VERSION 5.7 ;
  NOWIREEXTENSIONATPIN ON ;
  DIVIDERCHAR "/" ;
  BUSBITCHARS "[]" ;
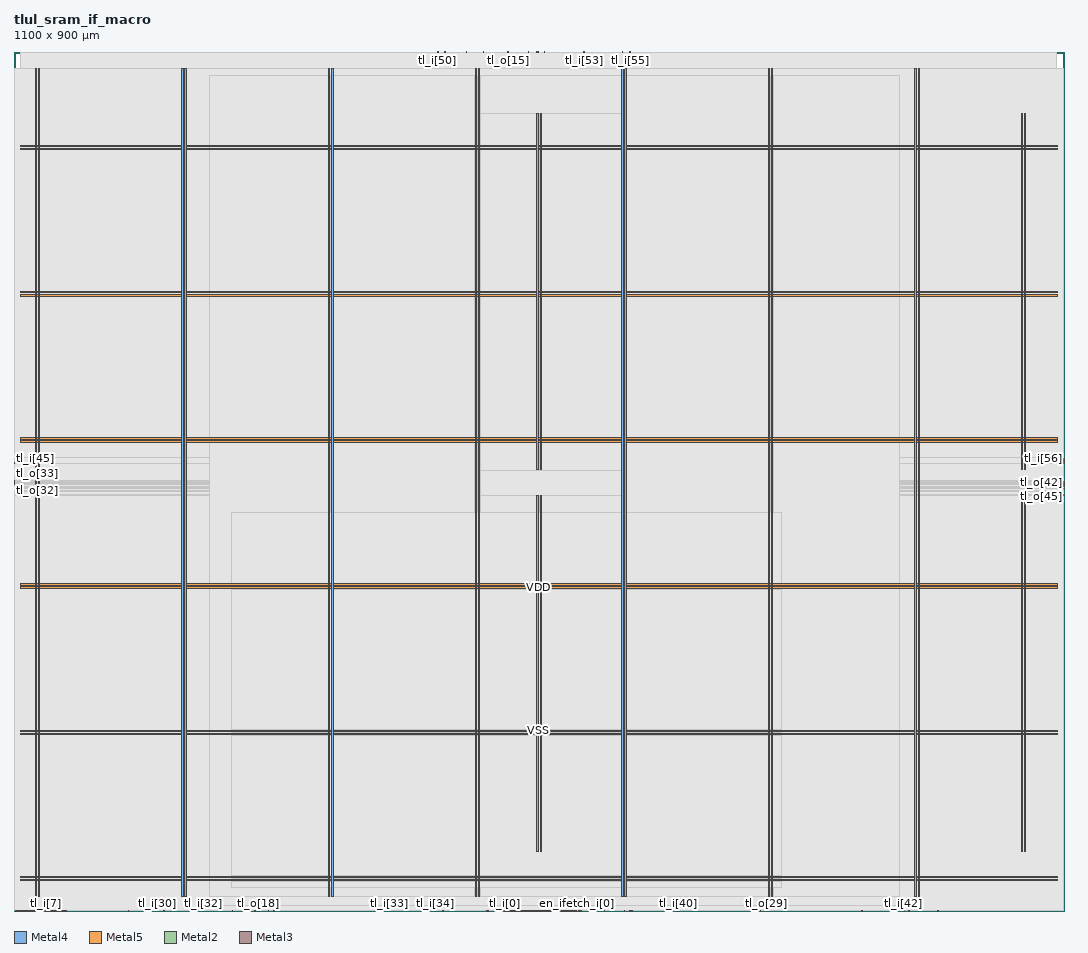
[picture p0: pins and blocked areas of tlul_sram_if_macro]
MACRO tlul_sram_if_macro
  CLASS BLOCK ;
  FOREIGN tlul_sram_if_macro ;
  ORIGIN 0.000 0.000 ;
  SIZE 1100.000 BY 900.000 ;
  PIN VDD
    DIRECTION INOUT ;
    USE POWER ;
    PORT
      LAYER Metal4 ;
        RECT 22.240 15.380 23.840 882.300 ;
    END
    PORT
      LAYER Metal4 ;
        RECT 175.840 15.380 177.440 882.300 ;
    END
    PORT
      LAYER Metal4 ;
        RECT 329.440 15.380 331.040 882.300 ;
    END
    PORT
      LAYER Metal4 ;
        RECT 483.040 15.380 484.640 882.300 ;
    END
    PORT
      LAYER Metal4 ;
        RECT 636.640 15.380 638.240 882.300 ;
    END
    PORT
      LAYER Metal4 ;
        RECT 790.240 15.380 791.840 882.300 ;
    END
    PORT
      LAYER Metal4 ;
        RECT 943.840 15.380 945.440 882.300 ;
    END
    PORT
      LAYER Metal5 ;
        RECT 6.720 31.530 1093.120 33.130 ;
    END
    PORT
      LAYER Metal5 ;
        RECT 6.720 184.710 1093.120 186.310 ;
    END
    PORT
      LAYER Metal5 ;
        RECT 6.720 337.890 1093.120 339.490 ;
    END
    PORT
      LAYER Metal5 ;
        RECT 6.720 491.070 1093.120 492.670 ;
    END
    PORT
      LAYER Metal5 ;
        RECT 6.720 644.250 1093.120 645.850 ;
    END
    PORT
      LAYER Metal5 ;
        RECT 6.720 797.430 1093.120 799.030 ;
    END
    PORT
      LAYER Metal4 ;
        RECT 547.720 62.420 549.320 435.420 ;
    END
    PORT
      LAYER Metal4 ;
        RECT 1055.080 462.260 1056.680 835.260 ;
    END
    PORT
      LAYER Metal4 ;
        RECT 547.720 462.260 549.320 835.260 ;
    END
    PORT
      LAYER Metal4 ;
        RECT 1055.080 62.420 1056.680 435.420 ;
    END
  END VDD
  PIN VSS
    DIRECTION INOUT ;
    USE GROUND ;
    PORT
      LAYER Metal4 ;
        RECT 25.540 15.380 27.140 882.300 ;
    END
    PORT
      LAYER Metal4 ;
        RECT 179.140 15.380 180.740 882.300 ;
    END
    PORT
      LAYER Metal4 ;
        RECT 332.740 15.380 334.340 882.300 ;
    END
    PORT
      LAYER Metal4 ;
        RECT 486.340 15.380 487.940 882.300 ;
    END
    PORT
      LAYER Metal4 ;
        RECT 639.940 15.380 641.540 882.300 ;
    END
    PORT
      LAYER Metal4 ;
        RECT 793.540 15.380 795.140 882.300 ;
    END
    PORT
      LAYER Metal4 ;
        RECT 947.140 15.380 948.740 882.300 ;
    END
    PORT
      LAYER Metal5 ;
        RECT 6.720 34.830 1093.120 36.430 ;
    END
    PORT
      LAYER Metal5 ;
        RECT 6.720 188.010 1093.120 189.610 ;
    END
    PORT
      LAYER Metal5 ;
        RECT 6.720 341.190 1093.120 342.790 ;
    END
    PORT
      LAYER Metal5 ;
        RECT 6.720 494.370 1093.120 495.970 ;
    END
    PORT
      LAYER Metal5 ;
        RECT 6.720 647.550 1093.120 649.150 ;
    END
    PORT
      LAYER Metal5 ;
        RECT 6.720 800.730 1093.120 802.330 ;
    END
    PORT
      LAYER Metal4 ;
        RECT 551.080 62.420 552.680 435.420 ;
    END
    PORT
      LAYER Metal4 ;
        RECT 1058.440 462.260 1060.040 835.260 ;
    END
    PORT
      LAYER Metal4 ;
        RECT 551.080 462.260 552.680 835.260 ;
    END
    PORT
      LAYER Metal4 ;
        RECT 1058.440 62.420 1060.040 435.420 ;
    END
  END VSS
  PIN clk_i
    DIRECTION INPUT ;
    USE SIGNAL ;
    ANTENNAGATEAREA 9.476000 ;
    PORT
      LAYER Metal2 ;
        RECT 228.480 0.000 229.040 0.560 ;
    END
  END clk_i
  PIN en_ifetch_i[0]
    DIRECTION INPUT ;
    USE SIGNAL ;
    ANTENNAGATEAREA 0.396000 ;
    PORT
      LAYER Metal2 ;
        RECT 589.120 0.000 589.680 0.560 ;
    END
  END en_ifetch_i[0]
  PIN en_ifetch_i[1]
    DIRECTION INPUT ;
    USE SIGNAL ;
    ANTENNAGATEAREA 0.396000 ;
    PORT
      LAYER Metal2 ;
        RECT 579.040 0.000 579.600 0.560 ;
    END
  END en_ifetch_i[1]
  PIN en_ifetch_i[2]
    DIRECTION INPUT ;
    USE SIGNAL ;
    ANTENNAGATEAREA 0.396000 ;
    PORT
      LAYER Metal2 ;
        RECT 565.600 0.000 566.160 0.560 ;
    END
  END en_ifetch_i[2]
  PIN en_ifetch_i[3]
    DIRECTION INPUT ;
    USE SIGNAL ;
    ANTENNAGATEAREA 0.396000 ;
    PORT
      LAYER Metal2 ;
        RECT 586.880 0.000 587.440 0.560 ;
    END
  END en_ifetch_i[3]
  PIN rst_ni
    DIRECTION INPUT ;
    USE SIGNAL ;
    ANTENNAGATEAREA 0.396000 ;
    PORT
      LAYER Metal2 ;
        RECT 581.280 0.000 581.840 0.560 ;
    END
  END rst_ni
  PIN tl_i[0]
    DIRECTION INPUT ;
    USE SIGNAL ;
    ANTENNAGATEAREA 0.396000 ;
    PORT
      LAYER Metal2 ;
        RECT 514.080 0.000 514.640 0.560 ;
    END
  END tl_i[0]
  PIN tl_i[100]
    DIRECTION INPUT ;
    USE SIGNAL ;
    ANTENNAGATEAREA 0.396000 ;
    PORT
      LAYER Metal2 ;
        RECT 516.320 0.000 516.880 0.560 ;
    END
  END tl_i[100]
  PIN tl_i[101]
    DIRECTION INPUT ;
    USE SIGNAL ;
    ANTENNAGATEAREA 0.396000 ;
    PORT
      LAYER Metal2 ;
        RECT 563.360 0.000 563.920 0.560 ;
    END
  END tl_i[101]
  PIN tl_i[102]
    DIRECTION INPUT ;
    USE SIGNAL ;
    ANTENNAGATEAREA 0.396000 ;
    PORT
      LAYER Metal2 ;
        RECT 543.200 0.000 543.760 0.560 ;
    END
  END tl_i[102]
  PIN tl_i[103]
    DIRECTION INPUT ;
    USE SIGNAL ;
    ANTENNAGATEAREA 0.396000 ;
    PORT
      LAYER Metal2 ;
        RECT 561.120 0.000 561.680 0.560 ;
    END
  END tl_i[103]
  PIN tl_i[104]
    DIRECTION INPUT ;
    USE SIGNAL ;
    ANTENNAGATEAREA 0.396000 ;
    PORT
      LAYER Metal2 ;
        RECT 567.840 0.000 568.400 0.560 ;
    END
  END tl_i[104]
  PIN tl_i[105]
    DIRECTION INPUT ;
    USE SIGNAL ;
    ANTENNAGATEAREA 0.396000 ;
    PORT
      LAYER Metal2 ;
        RECT 545.440 0.000 546.000 0.560 ;
    END
  END tl_i[105]
  PIN tl_i[106]
    DIRECTION INPUT ;
    USE SIGNAL ;
    ANTENNAGATEAREA 0.396000 ;
    PORT
      LAYER Metal2 ;
        RECT 540.960 0.000 541.520 0.560 ;
    END
  END tl_i[106]
  PIN tl_i[107]
    DIRECTION INPUT ;
    USE SIGNAL ;
    PORT
      LAYER Metal2 ;
        RECT 1.120 0.000 1.680 0.560 ;
    END
  END tl_i[107]
  PIN tl_i[108]
    DIRECTION INPUT ;
    USE SIGNAL ;
    PORT
      LAYER Metal2 ;
        RECT 2.240 0.000 2.800 0.560 ;
    END
  END tl_i[108]
  PIN tl_i[109]
    DIRECTION INPUT ;
    USE SIGNAL ;
    PORT
      LAYER Metal2 ;
        RECT 3.360 0.000 3.920 0.560 ;
    END
  END tl_i[109]
  PIN tl_i[10]
    DIRECTION INPUT ;
    USE SIGNAL ;
    PORT
      LAYER Metal2 ;
        RECT 4.480 0.000 5.040 0.560 ;
    END
  END tl_i[10]
  PIN tl_i[110]
    DIRECTION INPUT ;
    USE SIGNAL ;
    ANTENNAGATEAREA 0.396000 ;
    PORT
      LAYER Metal2 ;
        RECT 544.320 0.000 544.880 0.560 ;
    END
  END tl_i[110]
  PIN tl_i[111]
    DIRECTION INPUT ;
    USE SIGNAL ;
    ANTENNAGATEAREA 0.726000 ;
    PORT
      LAYER Metal2 ;
        RECT 512.960 0.000 513.520 0.560 ;
    END
  END tl_i[111]
  PIN tl_i[112]
    DIRECTION INPUT ;
    USE SIGNAL ;
    ANTENNAGATEAREA 0.726000 ;
    PORT
      LAYER Metal2 ;
        RECT 511.840 0.000 512.400 0.560 ;
    END
  END tl_i[112]
  PIN tl_i[113]
    DIRECTION INPUT ;
    USE SIGNAL ;
    ANTENNAGATEAREA 0.396000 ;
    PORT
      LAYER Metal2 ;
        RECT 524.160 0.000 524.720 0.560 ;
    END
  END tl_i[113]
  PIN tl_i[11]
    DIRECTION INPUT ;
    USE SIGNAL ;
    PORT
      LAYER Metal2 ;
        RECT 5.600 0.000 6.160 0.560 ;
    END
  END tl_i[11]
  PIN tl_i[12]
    DIRECTION INPUT ;
    USE SIGNAL ;
    PORT
      LAYER Metal2 ;
        RECT 6.720 0.000 7.280 0.560 ;
    END
  END tl_i[12]
  PIN tl_i[13]
    DIRECTION INPUT ;
    USE SIGNAL ;
    PORT
      LAYER Metal2 ;
        RECT 7.840 0.000 8.400 0.560 ;
    END
  END tl_i[13]
  PIN tl_i[14]
    DIRECTION INPUT ;
    USE SIGNAL ;
    PORT
      LAYER Metal2 ;
        RECT 8.960 0.000 9.520 0.560 ;
    END
  END tl_i[14]
  PIN tl_i[15]
    DIRECTION INPUT ;
    USE SIGNAL ;
    ANTENNAGATEAREA 0.396000 ;
    PORT
      LAYER Metal2 ;
        RECT 557.760 0.000 558.320 0.560 ;
    END
  END tl_i[15]
  PIN tl_i[16]
    DIRECTION INPUT ;
    USE SIGNAL ;
    ANTENNAGATEAREA 0.396000 ;
    PORT
      LAYER Metal2 ;
        RECT 583.520 0.000 584.080 0.560 ;
    END
  END tl_i[16]
  PIN tl_i[17]
    DIRECTION INPUT ;
    USE SIGNAL ;
    ANTENNAGATEAREA 0.396000 ;
    PORT
      LAYER Metal2 ;
        RECT 568.960 0.000 569.520 0.560 ;
    END
  END tl_i[17]
  PIN tl_i[18]
    DIRECTION INPUT ;
    USE SIGNAL ;
    ANTENNAGATEAREA 0.396000 ;
    PORT
      LAYER Metal2 ;
        RECT 555.520 0.000 556.080 0.560 ;
    END
  END tl_i[18]
  PIN tl_i[19]
    DIRECTION INPUT ;
    USE SIGNAL ;
    PORT
      LAYER Metal2 ;
        RECT 10.080 0.000 10.640 0.560 ;
    END
  END tl_i[19]
  PIN tl_i[1]
    DIRECTION INPUT ;
    USE SIGNAL ;
    PORT
      LAYER Metal2 ;
        RECT 11.200 0.000 11.760 0.560 ;
    END
  END tl_i[1]
  PIN tl_i[20]
    DIRECTION INPUT ;
    USE SIGNAL ;
    PORT
      LAYER Metal2 ;
        RECT 12.320 0.000 12.880 0.560 ;
    END
  END tl_i[20]
  PIN tl_i[21]
    DIRECTION INPUT ;
    USE SIGNAL ;
    PORT
      LAYER Metal2 ;
        RECT 13.440 0.000 14.000 0.560 ;
    END
  END tl_i[21]
  PIN tl_i[22]
    DIRECTION INPUT ;
    USE SIGNAL ;
    PORT
      LAYER Metal2 ;
        RECT 14.560 0.000 15.120 0.560 ;
    END
  END tl_i[22]
  PIN tl_i[23]
    DIRECTION INPUT ;
    USE SIGNAL ;
    PORT
      LAYER Metal2 ;
        RECT 15.680 0.000 16.240 0.560 ;
    END
  END tl_i[23]
  PIN tl_i[24]
    DIRECTION INPUT ;
    USE SIGNAL ;
    PORT
      LAYER Metal2 ;
        RECT 16.800 0.000 17.360 0.560 ;
    END
  END tl_i[24]
  PIN tl_i[25]
    DIRECTION INPUT ;
    USE SIGNAL ;
    PORT
      LAYER Metal2 ;
        RECT 17.920 0.000 18.480 0.560 ;
    END
  END tl_i[25]
  PIN tl_i[26]
    DIRECTION INPUT ;
    USE SIGNAL ;
    PORT
      LAYER Metal2 ;
        RECT 19.040 0.000 19.600 0.560 ;
    END
  END tl_i[26]
  PIN tl_i[27]
    DIRECTION INPUT ;
    USE SIGNAL ;
    PORT
      LAYER Metal2 ;
        RECT 20.160 0.000 20.720 0.560 ;
    END
  END tl_i[27]
  PIN tl_i[28]
    DIRECTION INPUT ;
    USE SIGNAL ;
    PORT
      LAYER Metal2 ;
        RECT 21.280 0.000 21.840 0.560 ;
    END
  END tl_i[28]
  PIN tl_i[29]
    DIRECTION INPUT ;
    USE SIGNAL ;
    ANTENNAGATEAREA 0.396000 ;
    PORT
      LAYER Metal2 ;
        RECT 119.840 0.000 120.400 0.560 ;
    END
  END tl_i[29]
  PIN tl_i[2]
    DIRECTION INPUT ;
    USE SIGNAL ;
    PORT
      LAYER Metal2 ;
        RECT 22.400 0.000 22.960 0.560 ;
    END
  END tl_i[2]
  PIN tl_i[30]
    DIRECTION INPUT ;
    USE SIGNAL ;
    ANTENNAGATEAREA 0.396000 ;
    PORT
      LAYER Metal2 ;
        RECT 150.080 0.000 150.640 0.560 ;
    END
  END tl_i[30]
  PIN tl_i[31]
    DIRECTION INPUT ;
    USE SIGNAL ;
    ANTENNAGATEAREA 0.396000 ;
    PORT
      LAYER Metal2 ;
        RECT 156.800 0.000 157.360 0.560 ;
    END
  END tl_i[31]
  PIN tl_i[32]
    DIRECTION INPUT ;
    USE SIGNAL ;
    ANTENNAGATEAREA 0.396000 ;
    PORT
      LAYER Metal2 ;
        RECT 198.240 0.000 198.800 0.560 ;
    END
  END tl_i[32]
  PIN tl_i[33]
    DIRECTION INPUT ;
    USE SIGNAL ;
    ANTENNAGATEAREA 0.396000 ;
    PORT
      LAYER Metal2 ;
        RECT 393.120 0.000 393.680 0.560 ;
    END
  END tl_i[33]
  PIN tl_i[34]
    DIRECTION INPUT ;
    USE SIGNAL ;
    ANTENNAGATEAREA 0.396000 ;
    PORT
      LAYER Metal2 ;
        RECT 441.280 0.000 441.840 0.560 ;
    END
  END tl_i[34]
  PIN tl_i[35]
    DIRECTION INPUT ;
    USE SIGNAL ;
    ANTENNAGATEAREA 0.396000 ;
    PORT
      LAYER Metal2 ;
        RECT 449.120 0.000 449.680 0.560 ;
    END
  END tl_i[35]
  PIN tl_i[36]
    DIRECTION INPUT ;
    USE SIGNAL ;
    ANTENNAGATEAREA 0.396000 ;
    PORT
      LAYER Metal2 ;
        RECT 496.160 0.000 496.720 0.560 ;
    END
  END tl_i[36]
  PIN tl_i[37]
    DIRECTION INPUT ;
    USE SIGNAL ;
    ANTENNAGATEAREA 0.396000 ;
    PORT
      LAYER Metal2 ;
        RECT 593.600 0.000 594.160 0.560 ;
    END
  END tl_i[37]
  PIN tl_i[38]
    DIRECTION INPUT ;
    USE SIGNAL ;
    ANTENNAGATEAREA 0.396000 ;
    PORT
      LAYER Metal2 ;
        RECT 639.520 0.000 640.080 0.560 ;
    END
  END tl_i[38]
  PIN tl_i[39]
    DIRECTION INPUT ;
    USE SIGNAL ;
    ANTENNAGATEAREA 0.396000 ;
    PORT
      LAYER Metal2 ;
        RECT 647.360 0.000 647.920 0.560 ;
    END
  END tl_i[39]
  PIN tl_i[3]
    DIRECTION INPUT ;
    USE SIGNAL ;
    PORT
      LAYER Metal2 ;
        RECT 23.520 0.000 24.080 0.560 ;
    END
  END tl_i[3]
  PIN tl_i[40]
    DIRECTION INPUT ;
    USE SIGNAL ;
    ANTENNAGATEAREA 0.396000 ;
    PORT
      LAYER Metal2 ;
        RECT 695.520 0.000 696.080 0.560 ;
    END
  END tl_i[40]
  PIN tl_i[41]
    DIRECTION INPUT ;
    USE SIGNAL ;
    ANTENNAGATEAREA 0.396000 ;
    PORT
      LAYER Metal2 ;
        RECT 888.160 0.000 888.720 0.560 ;
    END
  END tl_i[41]
  PIN tl_i[42]
    DIRECTION INPUT ;
    USE SIGNAL ;
    ANTENNAGATEAREA 0.396000 ;
    PORT
      LAYER Metal2 ;
        RECT 931.840 0.000 932.400 0.560 ;
    END
  END tl_i[42]
  PIN tl_i[43]
    DIRECTION INPUT ;
    USE SIGNAL ;
    ANTENNAGATEAREA 0.396000 ;
    PORT
      LAYER Metal2 ;
        RECT 937.440 0.000 938.000 0.560 ;
    END
  END tl_i[43]
  PIN tl_i[44]
    DIRECTION INPUT ;
    USE SIGNAL ;
    ANTENNAGATEAREA 0.396000 ;
    PORT
      LAYER Metal2 ;
        RECT 967.680 0.000 968.240 0.560 ;
    END
  END tl_i[44]
  PIN tl_i[45]
    DIRECTION INPUT ;
    USE SIGNAL ;
    ANTENNAGATEAREA 0.396000 ;
    PORT
      LAYER Metal3 ;
        RECT 0.000 473.760 0.560 474.320 ;
    END
  END tl_i[45]
  PIN tl_i[46]
    DIRECTION INPUT ;
    USE SIGNAL ;
    ANTENNAGATEAREA 0.396000 ;
    PORT
      LAYER Metal3 ;
        RECT 0.000 469.280 0.560 469.840 ;
    END
  END tl_i[46]
  PIN tl_i[47]
    DIRECTION INPUT ;
    USE SIGNAL ;
    ANTENNAGATEAREA 0.396000 ;
    PORT
      LAYER Metal3 ;
        RECT 0.000 470.400 0.560 470.960 ;
    END
  END tl_i[47]
  PIN tl_i[48]
    DIRECTION INPUT ;
    USE SIGNAL ;
    ANTENNAGATEAREA 0.396000 ;
    PORT
      LAYER Metal3 ;
        RECT 0.000 471.520 0.560 472.080 ;
    END
  END tl_i[48]
  PIN tl_i[49]
    DIRECTION INPUT ;
    USE SIGNAL ;
    ANTENNAGATEAREA 0.396000 ;
    PORT
      LAYER Metal3 ;
        RECT 0.000 472.640 0.560 473.200 ;
    END
  END tl_i[49]
  PIN tl_i[4]
    DIRECTION INPUT ;
    USE SIGNAL ;
    PORT
      LAYER Metal2 ;
        RECT 24.640 0.000 25.200 0.560 ;
    END
  END tl_i[4]
  PIN tl_i[50]
    DIRECTION INPUT ;
    USE SIGNAL ;
    ANTENNAGATEAREA 0.396000 ;
    PORT
      LAYER Metal2 ;
        RECT 443.520 899.440 444.080 900.000 ;
    END
  END tl_i[50]
  PIN tl_i[51]
    DIRECTION INPUT ;
    USE SIGNAL ;
    ANTENNAGATEAREA 0.396000 ;
    PORT
      LAYER Metal2 ;
        RECT 451.360 899.440 451.920 900.000 ;
    END
  END tl_i[51]
  PIN tl_i[52]
    DIRECTION INPUT ;
    USE SIGNAL ;
    ANTENNAGATEAREA 0.396000 ;
    PORT
      LAYER Metal2 ;
        RECT 491.680 899.440 492.240 900.000 ;
    END
  END tl_i[52]
  PIN tl_i[53]
    DIRECTION INPUT ;
    USE SIGNAL ;
    ANTENNAGATEAREA 0.396000 ;
    PORT
      LAYER Metal2 ;
        RECT 596.960 899.440 597.520 900.000 ;
    END
  END tl_i[53]
  PIN tl_i[54]
    DIRECTION INPUT ;
    USE SIGNAL ;
    ANTENNAGATEAREA 0.396000 ;
    PORT
      LAYER Metal2 ;
        RECT 637.280 899.440 637.840 900.000 ;
    END
  END tl_i[54]
  PIN tl_i[55]
    DIRECTION INPUT ;
    USE SIGNAL ;
    ANTENNAGATEAREA 0.396000 ;
    PORT
      LAYER Metal2 ;
        RECT 645.120 899.440 645.680 900.000 ;
    END
  END tl_i[55]
  PIN tl_i[56]
    DIRECTION INPUT ;
    USE SIGNAL ;
    ANTENNAGATEAREA 0.396000 ;
    PORT
      LAYER Metal3 ;
        RECT 1099.440 473.760 1100.000 474.320 ;
    END
  END tl_i[56]
  PIN tl_i[57]
    DIRECTION INPUT ;
    USE SIGNAL ;
    ANTENNAGATEAREA 0.396000 ;
    PORT
      LAYER Metal3 ;
        RECT 1099.440 471.520 1100.000 472.080 ;
    END
  END tl_i[57]
  PIN tl_i[58]
    DIRECTION INPUT ;
    USE SIGNAL ;
    ANTENNAGATEAREA 0.396000 ;
    PORT
      LAYER Metal3 ;
        RECT 1099.440 470.400 1100.000 470.960 ;
    END
  END tl_i[58]
  PIN tl_i[59]
    DIRECTION INPUT ;
    USE SIGNAL ;
    ANTENNAGATEAREA 0.396000 ;
    PORT
      LAYER Metal3 ;
        RECT 1099.440 469.280 1100.000 469.840 ;
    END
  END tl_i[59]
  PIN tl_i[5]
    DIRECTION INPUT ;
    USE SIGNAL ;
    PORT
      LAYER Metal2 ;
        RECT 25.760 0.000 26.320 0.560 ;
    END
  END tl_i[5]
  PIN tl_i[60]
    DIRECTION INPUT ;
    USE SIGNAL ;
    ANTENNAGATEAREA 0.396000 ;
    PORT
      LAYER Metal3 ;
        RECT 1099.440 472.640 1100.000 473.200 ;
    END
  END tl_i[60]
  PIN tl_i[61]
    DIRECTION INPUT ;
    USE SIGNAL ;
    ANTENNAGATEAREA 0.396000 ;
    PORT
      LAYER Metal2 ;
        RECT 527.520 0.000 528.080 0.560 ;
    END
  END tl_i[61]
  PIN tl_i[62]
    DIRECTION INPUT ;
    USE SIGNAL ;
    ANTENNAGATEAREA 0.396000 ;
    PORT
      LAYER Metal2 ;
        RECT 570.080 0.000 570.640 0.560 ;
    END
  END tl_i[62]
  PIN tl_i[63]
    DIRECTION INPUT ;
    USE SIGNAL ;
    ANTENNAGATEAREA 0.396000 ;
    PORT
      LAYER Metal2 ;
        RECT 523.040 0.000 523.600 0.560 ;
    END
  END tl_i[63]
  PIN tl_i[64]
    DIRECTION INPUT ;
    USE SIGNAL ;
    ANTENNAGATEAREA 0.396000 ;
    PORT
      LAYER Metal2 ;
        RECT 574.560 0.000 575.120 0.560 ;
    END
  END tl_i[64]
  PIN tl_i[65]
    DIRECTION INPUT ;
    USE SIGNAL ;
    ANTENNAGATEAREA 0.396000 ;
    PORT
      LAYER Metal2 ;
        RECT 533.120 0.000 533.680 0.560 ;
    END
  END tl_i[65]
  PIN tl_i[66]
    DIRECTION INPUT ;
    USE SIGNAL ;
    ANTENNAGATEAREA 0.396000 ;
    PORT
      LAYER Metal2 ;
        RECT 535.360 0.000 535.920 0.560 ;
    END
  END tl_i[66]
  PIN tl_i[67]
    DIRECTION INPUT ;
    USE SIGNAL ;
    ANTENNAGATEAREA 0.396000 ;
    PORT
      LAYER Metal2 ;
        RECT 547.680 0.000 548.240 0.560 ;
    END
  END tl_i[67]
  PIN tl_i[68]
    DIRECTION INPUT ;
    USE SIGNAL ;
    ANTENNAGATEAREA 0.396000 ;
    PORT
      LAYER Metal2 ;
        RECT 549.920 0.000 550.480 0.560 ;
    END
  END tl_i[68]
  PIN tl_i[69]
    DIRECTION INPUT ;
    USE SIGNAL ;
    ANTENNAGATEAREA 0.396000 ;
    PORT
      LAYER Metal2 ;
        RECT 519.680 0.000 520.240 0.560 ;
    END
  END tl_i[69]
  PIN tl_i[6]
    DIRECTION INPUT ;
    USE SIGNAL ;
    PORT
      LAYER Metal2 ;
        RECT 26.880 0.000 27.440 0.560 ;
    END
  END tl_i[6]
  PIN tl_i[70]
    DIRECTION INPUT ;
    USE SIGNAL ;
    ANTENNAGATEAREA 0.396000 ;
    PORT
      LAYER Metal2 ;
        RECT 532.000 0.000 532.560 0.560 ;
    END
  END tl_i[70]
  PIN tl_i[71]
    DIRECTION INPUT ;
    USE SIGNAL ;
    ANTENNAGATEAREA 0.396000 ;
    PORT
      LAYER Metal2 ;
        RECT 548.800 0.000 549.360 0.560 ;
    END
  END tl_i[71]
  PIN tl_i[72]
    DIRECTION INPUT ;
    USE SIGNAL ;
    ANTENNAGATEAREA 0.396000 ;
    PORT
      LAYER Metal2 ;
        RECT 526.400 0.000 526.960 0.560 ;
    END
  END tl_i[72]
  PIN tl_i[73]
    DIRECTION INPUT ;
    USE SIGNAL ;
    ANTENNAGATEAREA 0.396000 ;
    PORT
      LAYER Metal2 ;
        RECT 525.280 0.000 525.840 0.560 ;
    END
  END tl_i[73]
  PIN tl_i[74]
    DIRECTION INPUT ;
    USE SIGNAL ;
    ANTENNAGATEAREA 0.396000 ;
    PORT
      LAYER Metal2 ;
        RECT 518.560 0.000 519.120 0.560 ;
    END
  END tl_i[74]
  PIN tl_i[75]
    DIRECTION INPUT ;
    USE SIGNAL ;
    PORT
      LAYER Metal2 ;
        RECT 28.000 0.000 28.560 0.560 ;
    END
  END tl_i[75]
  PIN tl_i[76]
    DIRECTION INPUT ;
    USE SIGNAL ;
    PORT
      LAYER Metal2 ;
        RECT 29.120 0.000 29.680 0.560 ;
    END
  END tl_i[76]
  PIN tl_i[77]
    DIRECTION INPUT ;
    USE SIGNAL ;
    PORT
      LAYER Metal2 ;
        RECT 30.240 0.000 30.800 0.560 ;
    END
  END tl_i[77]
  PIN tl_i[78]
    DIRECTION INPUT ;
    USE SIGNAL ;
    PORT
      LAYER Metal2 ;
        RECT 31.360 0.000 31.920 0.560 ;
    END
  END tl_i[78]
  PIN tl_i[79]
    DIRECTION INPUT ;
    USE SIGNAL ;
    PORT
      LAYER Metal2 ;
        RECT 32.480 0.000 33.040 0.560 ;
    END
  END tl_i[79]
  PIN tl_i[7]
    DIRECTION INPUT ;
    USE SIGNAL ;
    PORT
      LAYER Metal2 ;
        RECT 33.600 0.000 34.160 0.560 ;
    END
  END tl_i[7]
  PIN tl_i[80]
    DIRECTION INPUT ;
    USE SIGNAL ;
    PORT
      LAYER Metal2 ;
        RECT 34.720 0.000 35.280 0.560 ;
    END
  END tl_i[80]
  PIN tl_i[81]
    DIRECTION INPUT ;
    USE SIGNAL ;
    PORT
      LAYER Metal2 ;
        RECT 35.840 0.000 36.400 0.560 ;
    END
  END tl_i[81]
  PIN tl_i[82]
    DIRECTION INPUT ;
    USE SIGNAL ;
    PORT
      LAYER Metal2 ;
        RECT 36.960 0.000 37.520 0.560 ;
    END
  END tl_i[82]
  PIN tl_i[83]
    DIRECTION INPUT ;
    USE SIGNAL ;
    PORT
      LAYER Metal2 ;
        RECT 38.080 0.000 38.640 0.560 ;
    END
  END tl_i[83]
  PIN tl_i[84]
    DIRECTION INPUT ;
    USE SIGNAL ;
    PORT
      LAYER Metal2 ;
        RECT 39.200 0.000 39.760 0.560 ;
    END
  END tl_i[84]
  PIN tl_i[85]
    DIRECTION INPUT ;
    USE SIGNAL ;
    PORT
      LAYER Metal2 ;
        RECT 40.320 0.000 40.880 0.560 ;
    END
  END tl_i[85]
  PIN tl_i[86]
    DIRECTION INPUT ;
    USE SIGNAL ;
    PORT
      LAYER Metal2 ;
        RECT 41.440 0.000 42.000 0.560 ;
    END
  END tl_i[86]
  PIN tl_i[87]
    DIRECTION INPUT ;
    USE SIGNAL ;
    PORT
      LAYER Metal2 ;
        RECT 42.560 0.000 43.120 0.560 ;
    END
  END tl_i[87]
  PIN tl_i[88]
    DIRECTION INPUT ;
    USE SIGNAL ;
    PORT
      LAYER Metal2 ;
        RECT 43.680 0.000 44.240 0.560 ;
    END
  END tl_i[88]
  PIN tl_i[89]
    DIRECTION INPUT ;
    USE SIGNAL ;
    PORT
      LAYER Metal2 ;
        RECT 44.800 0.000 45.360 0.560 ;
    END
  END tl_i[89]
  PIN tl_i[8]
    DIRECTION INPUT ;
    USE SIGNAL ;
    PORT
      LAYER Metal2 ;
        RECT 45.920 0.000 46.480 0.560 ;
    END
  END tl_i[8]
  PIN tl_i[90]
    DIRECTION INPUT ;
    USE SIGNAL ;
    PORT
      LAYER Metal2 ;
        RECT 47.040 0.000 47.600 0.560 ;
    END
  END tl_i[90]
  PIN tl_i[91]
    DIRECTION INPUT ;
    USE SIGNAL ;
    PORT
      LAYER Metal2 ;
        RECT 48.160 0.000 48.720 0.560 ;
    END
  END tl_i[91]
  PIN tl_i[92]
    DIRECTION INPUT ;
    USE SIGNAL ;
    PORT
      LAYER Metal2 ;
        RECT 49.280 0.000 49.840 0.560 ;
    END
  END tl_i[92]
  PIN tl_i[93]
    DIRECTION INPUT ;
    USE SIGNAL ;
    PORT
      LAYER Metal2 ;
        RECT 50.400 0.000 50.960 0.560 ;
    END
  END tl_i[93]
  PIN tl_i[94]
    DIRECTION INPUT ;
    USE SIGNAL ;
    PORT
      LAYER Metal2 ;
        RECT 51.520 0.000 52.080 0.560 ;
    END
  END tl_i[94]
  PIN tl_i[95]
    DIRECTION INPUT ;
    USE SIGNAL ;
    PORT
      LAYER Metal2 ;
        RECT 52.640 0.000 53.200 0.560 ;
    END
  END tl_i[95]
  PIN tl_i[96]
    DIRECTION INPUT ;
    USE SIGNAL ;
    PORT
      LAYER Metal2 ;
        RECT 53.760 0.000 54.320 0.560 ;
    END
  END tl_i[96]
  PIN tl_i[97]
    DIRECTION INPUT ;
    USE SIGNAL ;
    ANTENNAGATEAREA 0.396000 ;
    PORT
      LAYER Metal2 ;
        RECT 562.240 0.000 562.800 0.560 ;
    END
  END tl_i[97]
  PIN tl_i[98]
    DIRECTION INPUT ;
    USE SIGNAL ;
    ANTENNAGATEAREA 0.396000 ;
    PORT
      LAYER Metal2 ;
        RECT 553.280 0.000 553.840 0.560 ;
    END
  END tl_i[98]
  PIN tl_i[99]
    DIRECTION INPUT ;
    USE SIGNAL ;
    ANTENNAGATEAREA 0.396000 ;
    PORT
      LAYER Metal2 ;
        RECT 546.560 0.000 547.120 0.560 ;
    END
  END tl_i[99]
  PIN tl_i[9]
    DIRECTION INPUT ;
    USE SIGNAL ;
    PORT
      LAYER Metal2 ;
        RECT 54.880 0.000 55.440 0.560 ;
    END
  END tl_i[9]
  PIN tl_o[0]
    DIRECTION OUTPUT ;
    USE SIGNAL ;
    ANTENNADIFFAREA 0.897600 ;
    PORT
      LAYER Metal2 ;
        RECT 521.920 0.000 522.480 0.560 ;
    END
  END tl_o[0]
  PIN tl_o[10]
    DIRECTION OUTPUT ;
    USE SIGNAL ;
    ANTENNADIFFAREA 0.360800 ;
    PORT
      LAYER Metal2 ;
        RECT 551.040 0.000 551.600 0.560 ;
    END
  END tl_o[10]
  PIN tl_o[11]
    DIRECTION OUTPUT ;
    USE SIGNAL ;
    ANTENNADIFFAREA 0.360800 ;
    PORT
      LAYER Metal2 ;
        RECT 547.680 899.440 548.240 900.000 ;
    END
  END tl_o[11]
  PIN tl_o[12]
    DIRECTION OUTPUT ;
    USE SIGNAL ;
    ANTENNADIFFAREA 0.360800 ;
    PORT
      LAYER Metal2 ;
        RECT 585.760 0.000 586.320 0.560 ;
    END
  END tl_o[12]
  PIN tl_o[13]
    DIRECTION OUTPUT ;
    USE SIGNAL ;
    ANTENNADIFFAREA 0.360800 ;
    PORT
      LAYER Metal2 ;
        RECT 582.400 0.000 582.960 0.560 ;
    END
  END tl_o[13]
  PIN tl_o[14]
    DIRECTION OUTPUT ;
    USE SIGNAL ;
    ANTENNADIFFAREA 0.360800 ;
    PORT
      LAYER Metal2 ;
        RECT 534.240 0.000 534.800 0.560 ;
    END
  END tl_o[14]
  PIN tl_o[15]
    DIRECTION OUTPUT ;
    USE SIGNAL ;
    ANTENNADIFFAREA 0.360800 ;
    PORT
      LAYER Metal2 ;
        RECT 517.440 899.440 518.000 900.000 ;
    END
  END tl_o[15]
  PIN tl_o[16]
    DIRECTION OUTPUT ;
    USE SIGNAL ;
    ANTENNADIFFAREA 0.897600 ;
    PORT
      LAYER Metal2 ;
        RECT 252.000 0.000 252.560 0.560 ;
    END
  END tl_o[16]
  PIN tl_o[17]
    DIRECTION OUTPUT ;
    USE SIGNAL ;
    ANTENNADIFFAREA 0.897600 ;
    PORT
      LAYER Metal2 ;
        RECT 272.160 0.000 272.720 0.560 ;
    END
  END tl_o[17]
  PIN tl_o[18]
    DIRECTION OUTPUT ;
    USE SIGNAL ;
    ANTENNADIFFAREA 0.897600 ;
    PORT
      LAYER Metal2 ;
        RECT 255.360 0.000 255.920 0.560 ;
    END
  END tl_o[18]
  PIN tl_o[19]
    DIRECTION OUTPUT ;
    USE SIGNAL ;
    ANTENNADIFFAREA 0.897600 ;
    PORT
      LAYER Metal2 ;
        RECT 266.560 0.000 267.120 0.560 ;
    END
  END tl_o[19]
  PIN tl_o[1]
    DIRECTION OUTPUT ;
    USE SIGNAL ;
    ANTENNADIFFAREA 0.897600 ;
    PORT
      LAYER Metal2 ;
        RECT 556.640 0.000 557.200 0.560 ;
    END
  END tl_o[1]
  PIN tl_o[20]
    DIRECTION OUTPUT ;
    USE SIGNAL ;
    ANTENNADIFFAREA 0.897600 ;
    PORT
      LAYER Metal2 ;
        RECT 536.480 0.000 537.040 0.560 ;
    END
  END tl_o[20]
  PIN tl_o[21]
    DIRECTION OUTPUT ;
    USE SIGNAL ;
    ANTENNADIFFAREA 0.897600 ;
    PORT
      LAYER Metal2 ;
        RECT 537.600 0.000 538.160 0.560 ;
    END
  END tl_o[21]
  PIN tl_o[22]
    DIRECTION OUTPUT ;
    USE SIGNAL ;
    ANTENNADIFFAREA 0.897600 ;
    PORT
      LAYER Metal2 ;
        RECT 495.040 0.000 495.600 0.560 ;
    END
  END tl_o[22]
  PIN tl_o[23]
    DIRECTION OUTPUT ;
    USE SIGNAL ;
    ANTENNADIFFAREA 0.897600 ;
    PORT
      LAYER Metal2 ;
        RECT 542.080 0.000 542.640 0.560 ;
    END
  END tl_o[23]
  PIN tl_o[24]
    DIRECTION OUTPUT ;
    USE SIGNAL ;
    ANTENNADIFFAREA 0.897600 ;
    PORT
      LAYER Metal2 ;
        RECT 588.000 0.000 588.560 0.560 ;
    END
  END tl_o[24]
  PIN tl_o[25]
    DIRECTION OUTPUT ;
    USE SIGNAL ;
    ANTENNADIFFAREA 0.897600 ;
    PORT
      LAYER Metal2 ;
        RECT 591.360 0.000 591.920 0.560 ;
    END
  END tl_o[25]
  PIN tl_o[26]
    DIRECTION OUTPUT ;
    USE SIGNAL ;
    ANTENNADIFFAREA 0.897600 ;
    PORT
      LAYER Metal2 ;
        RECT 552.160 0.000 552.720 0.560 ;
    END
  END tl_o[26]
  PIN tl_o[27]
    DIRECTION OUTPUT ;
    USE SIGNAL ;
    ANTENNADIFFAREA 0.897600 ;
    PORT
      LAYER Metal2 ;
        RECT 560.000 0.000 560.560 0.560 ;
    END
  END tl_o[27]
  PIN tl_o[28]
    DIRECTION OUTPUT ;
    USE SIGNAL ;
    ANTENNADIFFAREA 0.897600 ;
    PORT
      LAYER Metal2 ;
        RECT 781.760 0.000 782.320 0.560 ;
    END
  END tl_o[28]
  PIN tl_o[29]
    DIRECTION OUTPUT ;
    USE SIGNAL ;
    ANTENNADIFFAREA 0.897600 ;
    PORT
      LAYER Metal2 ;
        RECT 788.480 0.000 789.040 0.560 ;
    END
  END tl_o[29]
  PIN tl_o[2]
    DIRECTION OUTPUT ;
    USE SIGNAL ;
    ANTENNADIFFAREA 0.360800 ;
    PORT
      LAYER Metal2 ;
        RECT 508.480 0.000 509.040 0.560 ;
    END
  END tl_o[2]
  PIN tl_o[30]
    DIRECTION OUTPUT ;
    USE SIGNAL ;
    ANTENNADIFFAREA 0.897600 ;
    PORT
      LAYER Metal2 ;
        RECT 778.400 0.000 778.960 0.560 ;
    END
  END tl_o[30]
  PIN tl_o[31]
    DIRECTION OUTPUT ;
    USE SIGNAL ;
    ANTENNADIFFAREA 0.897600 ;
    PORT
      LAYER Metal2 ;
        RECT 789.600 0.000 790.160 0.560 ;
    END
  END tl_o[31]
  PIN tl_o[32]
    DIRECTION OUTPUT ;
    USE SIGNAL ;
    ANTENNADIFFAREA 0.897600 ;
    PORT
      LAYER Metal3 ;
        RECT 0.000 440.160 0.560 440.720 ;
    END
  END tl_o[32]
  PIN tl_o[33]
    DIRECTION OUTPUT ;
    USE SIGNAL ;
    ANTENNADIFFAREA 0.897600 ;
    PORT
      LAYER Metal3 ;
        RECT 0.000 450.240 0.560 450.800 ;
    END
  END tl_o[33]
  PIN tl_o[34]
    DIRECTION OUTPUT ;
    USE SIGNAL ;
    ANTENNADIFFAREA 0.897600 ;
    PORT
      LAYER Metal3 ;
        RECT 0.000 448.000 0.560 448.560 ;
    END
  END tl_o[34]
  PIN tl_o[35]
    DIRECTION OUTPUT ;
    USE SIGNAL ;
    ANTENNADIFFAREA 0.897600 ;
    PORT
      LAYER Metal3 ;
        RECT 0.000 443.520 0.560 444.080 ;
    END
  END tl_o[35]
  PIN tl_o[36]
    DIRECTION OUTPUT ;
    USE SIGNAL ;
    ANTENNADIFFAREA 0.897600 ;
    PORT
      LAYER Metal3 ;
        RECT 0.000 446.880 0.560 447.440 ;
    END
  END tl_o[36]
  PIN tl_o[37]
    DIRECTION OUTPUT ;
    USE SIGNAL ;
    ANTENNADIFFAREA 0.897600 ;
    PORT
      LAYER Metal3 ;
        RECT 0.000 449.120 0.560 449.680 ;
    END
  END tl_o[37]
  PIN tl_o[38]
    DIRECTION OUTPUT ;
    USE SIGNAL ;
    ANTENNADIFFAREA 0.897600 ;
    PORT
      LAYER Metal2 ;
        RECT 444.640 899.440 445.200 900.000 ;
    END
  END tl_o[38]
  PIN tl_o[39]
    DIRECTION OUTPUT ;
    USE SIGNAL ;
    ANTENNADIFFAREA 0.897600 ;
    PORT
      LAYER Metal2 ;
        RECT 473.760 899.440 474.320 900.000 ;
    END
  END tl_o[39]
  PIN tl_o[3]
    DIRECTION OUTPUT ;
    USE SIGNAL ;
    ANTENNADIFFAREA 0.897600 ;
    PORT
      LAYER Metal2 ;
        RECT 530.880 0.000 531.440 0.560 ;
    END
  END tl_o[3]
  PIN tl_o[40]
    DIRECTION OUTPUT ;
    USE SIGNAL ;
    ANTENNADIFFAREA 0.897600 ;
    PORT
      LAYER Metal2 ;
        RECT 618.240 0.000 618.800 0.560 ;
    END
  END tl_o[40]
  PIN tl_o[41]
    DIRECTION OUTPUT ;
    USE SIGNAL ;
    ANTENNADIFFAREA 0.897600 ;
    PORT
      LAYER Metal2 ;
        RECT 645.120 0.000 645.680 0.560 ;
    END
  END tl_o[41]
  PIN tl_o[42]
    DIRECTION OUTPUT ;
    USE SIGNAL ;
    ANTENNADIFFAREA 0.897600 ;
    PORT
      LAYER Metal3 ;
        RECT 1099.440 449.120 1100.000 449.680 ;
    END
  END tl_o[42]
  PIN tl_o[43]
    DIRECTION OUTPUT ;
    USE SIGNAL ;
    ANTENNADIFFAREA 0.897600 ;
    PORT
      LAYER Metal3 ;
        RECT 1099.440 444.640 1100.000 445.200 ;
    END
  END tl_o[43]
  PIN tl_o[44]
    DIRECTION OUTPUT ;
    USE SIGNAL ;
    ANTENNADIFFAREA 0.897600 ;
    PORT
      LAYER Metal3 ;
        RECT 1099.440 445.760 1100.000 446.320 ;
    END
  END tl_o[44]
  PIN tl_o[45]
    DIRECTION OUTPUT ;
    USE SIGNAL ;
    ANTENNADIFFAREA 0.897600 ;
    PORT
      LAYER Metal3 ;
        RECT 1099.440 442.400 1100.000 442.960 ;
    END
  END tl_o[45]
  PIN tl_o[46]
    DIRECTION OUTPUT ;
    USE SIGNAL ;
    ANTENNADIFFAREA 0.897600 ;
    PORT
      LAYER Metal3 ;
        RECT 1099.440 446.880 1100.000 447.440 ;
    END
  END tl_o[46]
  PIN tl_o[47]
    DIRECTION OUTPUT ;
    USE SIGNAL ;
    ANTENNADIFFAREA 0.897600 ;
    PORT
      LAYER Metal3 ;
        RECT 1099.440 435.680 1100.000 436.240 ;
    END
  END tl_o[47]
  PIN tl_o[48]
    DIRECTION OUTPUT ;
    USE SIGNAL ;
    ANTENNADIFFAREA 0.360800 ;
    PORT
      LAYER Metal2 ;
        RECT 602.560 0.000 603.120 0.560 ;
    END
  END tl_o[48]
  PIN tl_o[49]
    DIRECTION OUTPUT ;
    USE SIGNAL ;
    ANTENNADIFFAREA 0.897600 ;
    PORT
      LAYER Metal2 ;
        RECT 564.480 0.000 565.040 0.560 ;
    END
  END tl_o[49]
  PIN tl_o[4]
    DIRECTION OUTPUT ;
    USE SIGNAL ;
    ANTENNADIFFAREA 0.360800 ;
    PORT
      LAYER Metal2 ;
        RECT 539.840 0.000 540.400 0.560 ;
    END
  END tl_o[4]
  PIN tl_o[50]
    DIRECTION OUTPUT ;
    USE SIGNAL ;
    ANTENNADIFFAREA 0.897600 ;
    PORT
      LAYER Metal2 ;
        RECT 572.320 0.000 572.880 0.560 ;
    END
  END tl_o[50]
  PIN tl_o[51]
    DIRECTION OUTPUT ;
    USE SIGNAL ;
    ANTENNADIFFAREA 0.897600 ;
    PORT
      LAYER Metal2 ;
        RECT 515.200 0.000 515.760 0.560 ;
    END
  END tl_o[51]
  PIN tl_o[52]
    DIRECTION OUTPUT ;
    USE SIGNAL ;
    ANTENNADIFFAREA 0.897600 ;
    PORT
      LAYER Metal2 ;
        RECT 554.400 0.000 554.960 0.560 ;
    END
  END tl_o[52]
  PIN tl_o[53]
    DIRECTION OUTPUT ;
    USE SIGNAL ;
    ANTENNADIFFAREA 0.897600 ;
    PORT
      LAYER Metal2 ;
        RECT 575.680 0.000 576.240 0.560 ;
    END
  END tl_o[53]
  PIN tl_o[54]
    DIRECTION OUTPUT ;
    USE SIGNAL ;
    ANTENNADIFFAREA 0.897600 ;
    PORT
      LAYER Metal2 ;
        RECT 538.720 0.000 539.280 0.560 ;
    END
  END tl_o[54]
  PIN tl_o[55]
    DIRECTION OUTPUT ;
    USE SIGNAL ;
    ANTENNADIFFAREA 0.897600 ;
    PORT
      LAYER Metal2 ;
        RECT 576.800 0.000 577.360 0.560 ;
    END
  END tl_o[55]
  PIN tl_o[56]
    DIRECTION OUTPUT ;
    USE SIGNAL ;
    ANTENNADIFFAREA 0.897600 ;
    PORT
      LAYER Metal2 ;
        RECT 566.720 0.000 567.280 0.560 ;
    END
  END tl_o[56]
  PIN tl_o[57]
    DIRECTION OUTPUT ;
    USE SIGNAL ;
    ANTENNADIFFAREA 0.897600 ;
    PORT
      LAYER Metal2 ;
        RECT 558.880 0.000 559.440 0.560 ;
    END
  END tl_o[57]
  PIN tl_o[58]
    DIRECTION OUTPUT ;
    USE SIGNAL ;
    ANTENNADIFFAREA 0.897600 ;
    PORT
      LAYER Metal2 ;
        RECT 577.920 0.000 578.480 0.560 ;
    END
  END tl_o[58]
  PIN tl_o[59]
    DIRECTION OUTPUT ;
    USE SIGNAL ;
    ANTENNADIFFAREA 0.360800 ;
    PORT
      LAYER Metal2 ;
        RECT 548.800 899.440 549.360 900.000 ;
    END
  END tl_o[59]
  PIN tl_o[5]
    DIRECTION OUTPUT ;
    USE SIGNAL ;
    ANTENNADIFFAREA 0.897600 ;
    PORT
      LAYER Metal2 ;
        RECT 529.760 0.000 530.320 0.560 ;
    END
  END tl_o[5]
  PIN tl_o[60]
    DIRECTION OUTPUT ;
    USE SIGNAL ;
    ANTENNADIFFAREA 0.360800 ;
    PORT
      LAYER Metal2 ;
        RECT 520.800 0.000 521.360 0.560 ;
    END
  END tl_o[60]
  PIN tl_o[61]
    DIRECTION OUTPUT ;
    USE SIGNAL ;
    ANTENNADIFFAREA 0.360800 ;
    PORT
      LAYER Metal2 ;
        RECT 538.720 899.440 539.280 900.000 ;
    END
  END tl_o[61]
  PIN tl_o[62]
    DIRECTION OUTPUT ;
    USE SIGNAL ;
    ANTENNADIFFAREA 0.897600 ;
    PORT
      LAYER Metal2 ;
        RECT 517.440 0.000 518.000 0.560 ;
    END
  END tl_o[62]
  PIN tl_o[63]
    DIRECTION OUTPUT ;
    USE SIGNAL ;
    ANTENNADIFFAREA 0.360800 ;
    PORT
      LAYER Metal2 ;
        RECT 580.160 0.000 580.720 0.560 ;
    END
  END tl_o[63]
  PIN tl_o[64]
    DIRECTION OUTPUT ;
    USE SIGNAL ;
    ANTENNADIFFAREA 0.360800 ;
    PORT
      LAYER Metal2 ;
        RECT 571.200 0.000 571.760 0.560 ;
    END
  END tl_o[64]
  PIN tl_o[65]
    DIRECTION OUTPUT ;
    USE SIGNAL ;
    ANTENNADIFFAREA 0.897600 ;
    PORT
      LAYER Metal2 ;
        RECT 584.640 0.000 585.200 0.560 ;
    END
  END tl_o[65]
  PIN tl_o[6]
    DIRECTION OUTPUT ;
    USE SIGNAL ;
    ANTENNADIFFAREA 0.360800 ;
    PORT
      LAYER Metal2 ;
        RECT 573.440 0.000 574.000 0.560 ;
    END
  END tl_o[6]
  PIN tl_o[7]
    DIRECTION OUTPUT ;
    USE SIGNAL ;
    ANTENNADIFFAREA 0.897600 ;
    PORT
      LAYER Metal2 ;
        RECT 256.480 0.000 257.040 0.560 ;
    END
  END tl_o[7]
  PIN tl_o[8]
    DIRECTION OUTPUT ;
    USE SIGNAL ;
    ANTENNADIFFAREA 0.360800 ;
    PORT
      LAYER Metal2 ;
        RECT 528.640 0.000 529.200 0.560 ;
    END
  END tl_o[8]
  PIN tl_o[9]
    DIRECTION OUTPUT ;
    USE SIGNAL ;
    ANTENNADIFFAREA 0.360800 ;
    PORT
      LAYER Metal2 ;
        RECT 555.520 899.440 556.080 900.000 ;
    END
  END tl_o[9]
  OBS
      LAYER Nwell ;
        RECT 6.290 15.250 1093.550 882.430 ;
      LAYER Metal1 ;
        RECT 6.720 15.380 1093.120 882.300 ;
      LAYER Metal2 ;
        RECT 6.300 899.140 443.220 899.440 ;
        RECT 445.500 899.140 451.060 899.440 ;
        RECT 452.220 899.140 473.460 899.440 ;
        RECT 474.620 899.140 491.380 899.440 ;
        RECT 492.540 899.140 517.140 899.440 ;
        RECT 518.300 899.140 538.420 899.440 ;
        RECT 539.580 899.140 547.380 899.440 ;
        RECT 549.660 899.140 555.220 899.440 ;
        RECT 556.380 899.140 596.660 899.440 ;
        RECT 597.820 899.140 636.980 899.440 ;
        RECT 638.140 899.140 644.820 899.440 ;
        RECT 645.980 899.140 1092.420 899.440 ;
        RECT 6.300 0.860 1092.420 899.140 ;
        RECT 55.740 0.090 119.540 0.860 ;
        RECT 120.700 0.090 149.780 0.860 ;
        RECT 150.940 0.090 156.500 0.860 ;
        RECT 157.660 0.090 197.940 0.860 ;
        RECT 199.100 0.090 228.180 0.860 ;
        RECT 229.340 0.090 251.700 0.860 ;
        RECT 252.860 0.090 255.060 0.860 ;
        RECT 257.340 0.090 266.260 0.860 ;
        RECT 267.420 0.090 271.860 0.860 ;
        RECT 273.020 0.090 392.820 0.860 ;
        RECT 393.980 0.090 440.980 0.860 ;
        RECT 442.140 0.090 448.820 0.860 ;
        RECT 449.980 0.090 494.740 0.860 ;
        RECT 497.020 0.090 508.180 0.860 ;
        RECT 509.340 0.090 511.540 0.860 ;
        RECT 589.980 0.090 591.060 0.860 ;
        RECT 592.220 0.090 593.300 0.860 ;
        RECT 594.460 0.090 602.260 0.860 ;
        RECT 603.420 0.090 617.940 0.860 ;
        RECT 619.100 0.090 639.220 0.860 ;
        RECT 640.380 0.090 644.820 0.860 ;
        RECT 645.980 0.090 647.060 0.860 ;
        RECT 648.220 0.090 695.220 0.860 ;
        RECT 696.380 0.090 778.100 0.860 ;
        RECT 779.260 0.090 781.460 0.860 ;
        RECT 782.620 0.090 788.180 0.860 ;
        RECT 790.460 0.090 887.860 0.860 ;
        RECT 889.020 0.090 931.540 0.860 ;
        RECT 932.700 0.090 937.140 0.860 ;
        RECT 938.300 0.090 967.380 0.860 ;
        RECT 968.540 0.090 1092.420 0.860 ;
      LAYER Metal3 ;
        RECT 0.560 474.620 1099.440 882.980 ;
        RECT 0.860 468.980 1099.140 474.620 ;
        RECT 0.560 451.100 1099.440 468.980 ;
        RECT 0.860 449.980 1099.440 451.100 ;
        RECT 0.860 448.820 1099.140 449.980 ;
        RECT 0.860 447.740 1099.440 448.820 ;
        RECT 0.860 446.580 1099.140 447.740 ;
        RECT 0.560 444.380 1099.140 446.580 ;
        RECT 0.860 444.340 1099.140 444.380 ;
        RECT 0.860 443.260 1099.440 444.340 ;
        RECT 0.860 443.220 1099.140 443.260 ;
        RECT 0.560 442.100 1099.140 443.220 ;
        RECT 0.560 441.020 1099.440 442.100 ;
        RECT 0.860 439.860 1099.440 441.020 ;
        RECT 0.560 436.540 1099.440 439.860 ;
        RECT 0.560 435.380 1099.140 436.540 ;
        RECT 0.560 0.140 1099.440 435.380 ;
      LAYER Metal4 ;
        RECT 205.100 15.080 329.140 875.190 ;
        RECT 331.340 15.080 332.440 875.190 ;
        RECT 334.640 15.080 482.740 875.190 ;
        RECT 484.940 15.080 486.040 875.190 ;
        RECT 488.240 835.560 636.340 875.190 ;
        RECT 488.240 461.960 547.420 835.560 ;
        RECT 549.620 461.960 550.780 835.560 ;
        RECT 552.980 461.960 636.340 835.560 ;
        RECT 488.240 435.720 636.340 461.960 ;
        RECT 488.240 62.120 547.420 435.720 ;
        RECT 549.620 62.120 550.780 435.720 ;
        RECT 552.980 62.120 636.340 435.720 ;
        RECT 488.240 15.080 636.340 62.120 ;
        RECT 638.540 15.080 639.640 875.190 ;
        RECT 641.840 15.080 789.940 875.190 ;
        RECT 792.140 15.080 793.240 875.190 ;
        RECT 795.440 15.080 927.780 875.190 ;
        RECT 205.100 5.690 927.780 15.080 ;
      LAYER Metal5 ;
        RECT 227.980 343.390 804.100 417.370 ;
        RECT 227.980 340.090 804.100 340.590 ;
        RECT 227.980 190.210 804.100 337.290 ;
        RECT 227.980 186.910 804.100 187.410 ;
        RECT 227.980 37.030 804.100 184.110 ;
        RECT 227.980 33.730 804.100 34.230 ;
        RECT 227.980 24.530 804.100 30.930 ;
  END
END tlul_sram_if_macro
END LIBRARY

